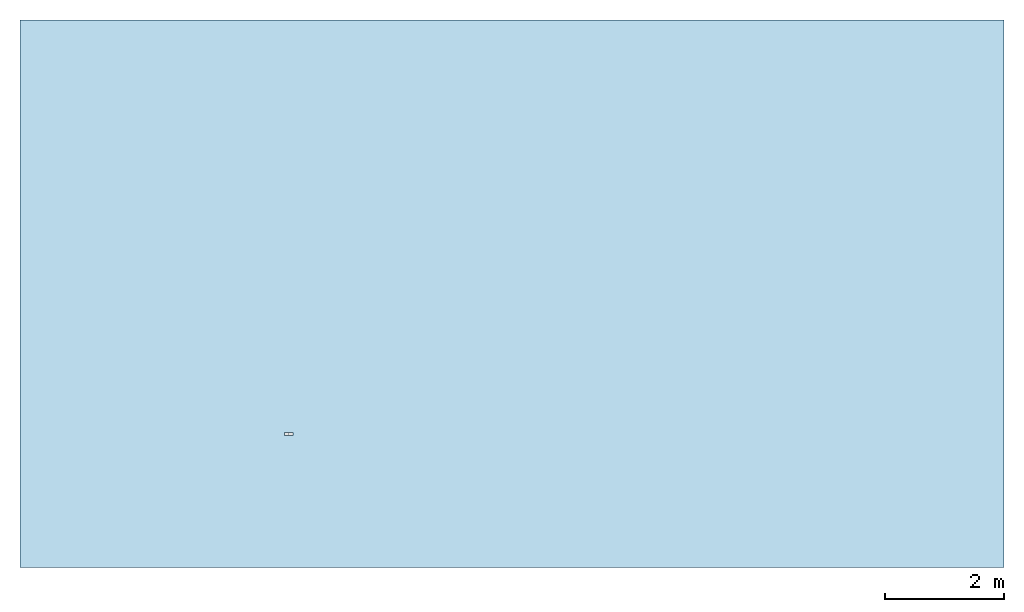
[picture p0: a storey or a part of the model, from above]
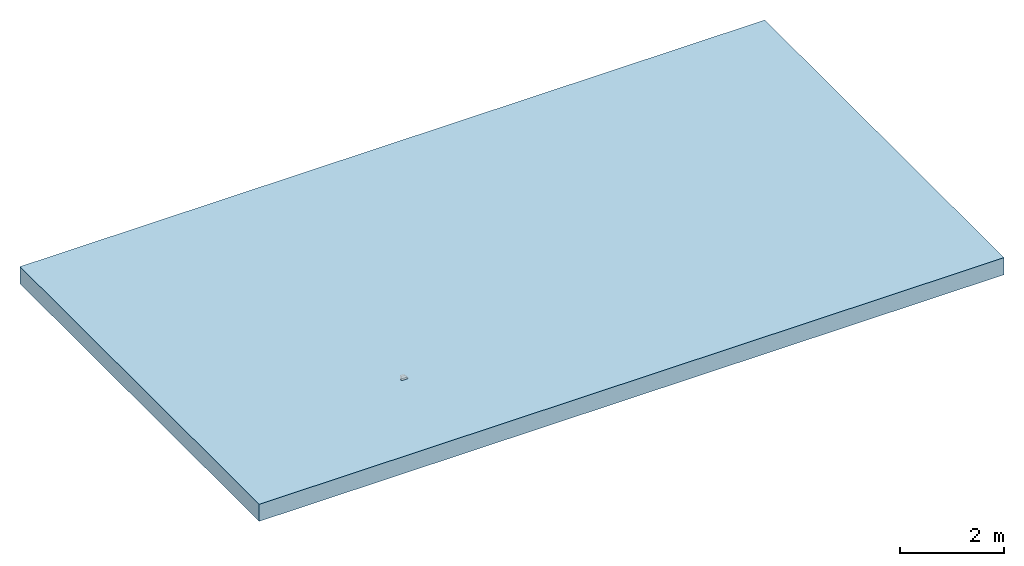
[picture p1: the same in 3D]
Properties of the parts of a building model (IFC2X3)

# File
Description: ViewDefinition [CoordinationView]
File name: 4961 - Closing end cap.ifc
Time: 2013-09-02T12:29:00
Written by: Autodesk Revit 2013
Made in: 20120221_2030(x64)

# IfcProject, Project Number
LongName: Project Name; Phase: Project Status

# IfcSite, Default
RefLatitude: 42, 21, 30, 344238; RefLongitude: -71, -3, -35, -194702; RefElevation: 0 mm

# IfcBuilding
Pset_BuildingCommon - NumberOfStoreys: 1
Other - Project Issue Date: Issue Date; Client Name: Owner; Project Status: Project Status; Project Number: Project Number; Project Address: ## Street City, State Zip; Project Name: Project Name

# IfcBuildingStorey, Level 1
LongName: Level 1; Elevation: 0 mm
Constraints - Elevation Base: 0; Elevation: 0 mm
Graphics - Symbol at End 1 Default: no; Color: 0; Symbol at End 2 Default: yes; Line Weight: 1; Symbol: M_Level Head - Circle: M_Level Head - Circle; Line Pattern: Center
Identity Data - Name: Level 1; Structural: no; Building Story: yes
Dimensions - Computation Height: 0 mm

# IfcBuildingElementProxy: 4961 - Closing end cap, Civil-Drainage-Channel-ACO-KerbDrain-SP280:4961 - Closing end cap:4961 - Closing end cap:311063
In: Level 1
Material: ACO Polymer Concrete.
Dimensions - Volume: 3458598 mm3; Void Depth: -380 mm; Endcap void: 1000 mm; Void Length: 50 mm; AccessDepth: 2000 mm; Void Width: 150 mm; Access hole: 2 mm
Phasing - Phase Created: New Construction
Constraints - Moves With Nearby Elements: no; Level: Level: Level 1
Pset_BuildingElementProxyCommon - Reference: 4961 - Closing end cap
Identity Data - Cost: 0; e-mail Sales: customersupport@aco.co.uk; Telephone: +44 (0)1462 816666; Installation guidelines: http://www.aco.co.uk/download.php?id=120; Maintenance guidelines: http://www.aco.co.uk/download.php?id=120; URL: www.aco.co.uk; Model Description: Combined kerb and drainage system; Manufacturer: ACO Technologies plc - ACO Water Management Division; Fax: +44 (0)1462 815895; Product Page URL: http://www.aco.co.uk/product_detail.php?id=3; Assembly Code: D2040; e-mail Technical: technical@aco.co.uk; Address: ACO Business Park, Hitchin Road, Shefford, Bedfordshire, United Kingdom SG17 5TE; Product brochure: http://www.aco.co.uk/download.php?id=120; Price: POA - contact ACO; Model: ACO KerbDrain SP280; OmniClass Title: Rainwater Removal; Product Code: 4961; Type Comments: ACO KerbDrain SP280 splayed closing end cap; Assembly Description: Rain Water Drainage; OmniClass Number: 23.70.50.24
Materials and Finishes - Access Cover/Frame Finish: N/A; Access Cover/Frame Colour: N/A; Channel Colour: N/A; Channel Material: N/A; Connection Pipe Material: N/A; End Cap Colour: Grey; Access Cover/Frame Material: N/A; Connection Pipe Material Colour: N/A; End Cap Material: Vienite® Synthetic Resin Concrete
Construction - SP280 - 1000: no; Centre Stone: no; LH transition unit: no; LH drop kerb: no; Access Unit: no; perforated centre stone: no; RH transition unit: no; RH inlet/outlet end cap: no; SP280-500: no; RH drop kerb: no; LH inlet/outlet end cap: no; Closing end cap: yes
General - TagNumber: 0.000000; SerialNumber: 0.000000
Data - Concrete Surround Volume - Load Class A 15 - D 400 - Concrete Pavement: N/A; Installation - Concrete Grade: N/A; Drainage Slot Intake area: N/A; Connection Pipe O.D: N/A; Product Weight: 7.4 Kg; Product Dimensions: 50mm x 150mm x 480mm (LxWxH); Hydraulic Performance: N/A; Channel C.S.A: N/A; Load Class: N/A; Invert Depth: N/A; Concrete Surround Volume - Load Class A 15 - D 400 - Grass or Asphalt Pavement: N/A; ACO Hydraulic Design Software: N/A; Drainage Slot Width: N/A; Product Standard: N/A
Other - Revision: 1; CreatedBy: www.aco.co.uk
Green Building Properties - Access Cover/Frame Recyclable: N/A; End Cap Recycled Material Content: 20% minimum; Channel Recyclable: N/A; Channel Recycled Material Content: N/A; End Cap Recyclable: Fully recyclable; Access Cover/Frame Recycled Material Content: N/A

# IfcOpeningElement: Recess (3)
In: Level 1
Dimensions - Volume: 60585150000 mm3; Area: 151470000 mm2; Perimeter: 51360 mm; Thickness: 400 mm
Constraints - Room Bounding: yes; Level: Level: Level 1; Related to Mass: no; Height Offset From Level: 0 mm
Phasing - Phase Created: New Construction
Structural - Structural: no; Enable Analytical Model: no
Analytical Properties - Absorptance: 0.1; Roughness: 1
Graphics - Coarse Scale Fill Color: 0
Construction - Function: 0; Default Thickness: 400 mm
Materials and Finishes - Structural Material: Plant

# IfcSlab: Floor:Generic Floor - 400mm, Floor:Generic Floor - 400mm:193825
In: Level 1
PredefinedType: FLOOR; Material: Plant 400 mm
Dimensions - Volume: 60585150000 mm3; Area: 151470000 mm2; Perimeter: 51360 mm; Thickness: 400 mm
Constraints - Room Bounding: yes; Level: Level: Level 1; Related to Mass: no; Height Offset From Level: 0 mm
Phasing - Phase Created: New Construction
Structural - Structural: no; Enable Analytical Model: no
Pset_SlabCommon - Reference: Generic Floor - 400mm; IsExternal: no; LoadBearing: yes
Analytical Properties - Absorptance: 0.1; Roughness: 1
Graphics - Coarse Scale Fill Color: 0
Construction - Function: 0; Default Thickness: 400 mm
Materials and Finishes - Structural Material: Plant
